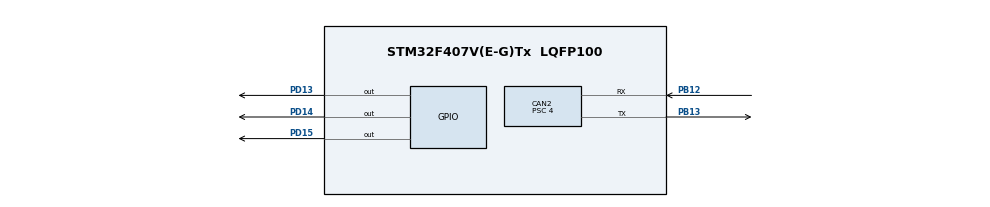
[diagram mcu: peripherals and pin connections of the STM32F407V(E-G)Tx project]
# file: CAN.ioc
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CAN2.BS1=CAN_BS1_8TQ
CAN2.BS2=CAN_BS2_7TQ
CAN2.CalculateBaudRate=250000
CAN2.CalculateTimeBit=4000
CAN2.CalculateTimeQuantum=250.0
CAN2.Prescaler=4
Mcu.Family=STM32F4
Mcu.Name=STM32F407V(E-G)Tx
Mcu.Package=LQFP100
NVIC.CAN2_RX0_IRQn=true\:0\:0\:false\:false\:true\:true\:true\:true
NVIC.PriorityGroup=NVIC_PRIORITYGROUP_4
PB12.Mode=CAN_Activate
PB12.Signal=CAN2_RX
PB13.Mode=CAN_Activate
PB13.Signal=CAN2_TX
PD13.Signal=GPIO_Output
PD14.Signal=GPIO_Output
PD15.Signal=GPIO_Output
ProjectManager.HeapSize=0x200
ProjectManager.StackSize=0x400
ProjectManager.TargetToolchain=STM32CubeIDE
RCC.AHBFreq_Value=16000000
RCC.APB1Freq_Value=16000000
RCC.APB2Freq_Value=16000000
RCC.CortexFreq_Value=16000000
RCC.HSE_VALUE=25000000
RCC.HSI_VALUE=16000000
RCC.LSE_VALUE=32768
RCC.SYSCLKFreq_VALUE=16000000
RCC.VCOOutputFreq_Value=192000000
board=custom

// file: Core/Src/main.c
/* USER CODE BEGIN Header */
/**
  ******************************************************************************
  * @file           : main.c
  * @brief          : Main program body
  ******************************************************************************
  * @attention
  *
  * Copyright (c) 2023 STMicroelectronics.
  * All rights reserved.
  *
  * This software is licensed under terms that can be found in the LICENSE file
  * in the root directory of this software component.
  * If no LICENSE file comes with this software, it is provided AS-IS.
  *
  ******************************************************************************
  */
/* USER CODE END Header */
#include "main.h"

CAN_HandleTypeDef hcan2;

/* USER CODE BEGIN PV */

// We need to define the CAN transmit header
// & the array that will contain the data to transmit
// & the mailbox where the data is added to before being sent
CAN_TxHeaderTypeDef   TxHeader;
CAN_RxHeaderTypeDef   RxHeader;

uint8_t               TxData[8];
uint32_t              TxMailbox;
uint8_t               RxData[8];
/* USER CODE END PV */

void SystemClock_Config(void);
static void MX_GPIO_Init(void);
static void MX_CAN2_Init(void);

/* USER CODE BEGIN 0 */

void HAL_CAN_RxFifo0MsgPendingCallback(CAN_HandleTypeDef *hcan2)
{
  if (HAL_CAN_GetRxMessage(hcan2, CAN_RX_FIFO0, &RxHeader, RxData) != HAL_OK)
  {
    Error_Handler();
  }

  HAL_GPIO_TogglePin(GPIOD,GPIO_PIN_13);
  TxData[0] = RxData[0];

  if (HAL_CAN_AddTxMessage(hcan2, &TxHeader, TxData, &TxMailbox) != HAL_OK)
  	  {
  		/* Transmission request Error */
  		Error_Handler();
  	  }

}

/* USER CODE END 0 */

int main(void)
{
  /* USER CODE BEGIN 1 */

	// The CAN clock must be enabled
  __HAL_RCC_CAN2_CLK_ENABLE();

  /* USER CODE END 1 */

  /* MCU Configuration--------------------------------------------------------*/

  /* Reset of all peripherals, Initializes the Flash interface and the Systick. */
  HAL_Init();

  /* Configure the system clock */
  SystemClock_Config();

  /* Initialize all configured peripherals */
  MX_GPIO_Init();
  MX_CAN2_Init();

  /* Infinite loop */
  /* USER CODE BEGIN WHILE */
  while (1)
  {

//	  // Enable channel
//	  TxData[0] = 0x1C;
//
//	  /* Start the Transmission process */
//	  // By using the HAL_CAN_ADD_TxMessage(args), a CAN message will try to be sent
//	  if (HAL_CAN_AddTxMessage(&hcan2, &TxHeader, TxData, &TxMailbox) != HAL_OK)
//	  {
//		/* Transmission request Error */
//		Error_Handler();
//	  }
	  HAL_GPIO_TogglePin(GPIOD, GPIO_PIN_13);
	  HAL_Delay(1);

    /* USER CODE END WHILE */

  }
}

void SystemClock_Config(void)
{
  RCC_OscInitTypeDef RCC_OscInitStruct = {0};
  RCC_ClkInitTypeDef RCC_ClkInitStruct = {0};

  /** Configure the main internal regulator output voltage
  */
  __HAL_RCC_PWR_CLK_ENABLE();
  __HAL_PWR_VOLTAGESCALING_CONFIG(PWR_REGULATOR_VOLTAGE_SCALE1);

  /** Initializes the RCC Oscillators according to the specified parameters
  * in the RCC_OscInitTypeDef structure.
  */
  RCC_OscInitStruct.OscillatorType = RCC_OSCILLATORTYPE_HSI|RCC_OSCILLATORTYPE_HSE;
  RCC_OscInitStruct.HSEState = RCC_HSE_ON;
  RCC_OscInitStruct.HSIState = RCC_HSI_ON;
  RCC_OscInitStruct.HSICalibrationValue = RCC_HSICALIBRATION_DEFAULT;
  RCC_OscInitStruct.PLL.PLLState = RCC_PLL_ON;
  RCC_OscInitStruct.PLL.PLLSource = RCC_PLLSOURCE_HSE;
  RCC_OscInitStruct.PLL.PLLM = 4;
  RCC_OscInitStruct.PLL.PLLN = 168;
  RCC_OscInitStruct.PLL.PLLP = RCC_PLLP_DIV2;
  RCC_OscInitStruct.PLL.PLLQ = 4;
  if (HAL_RCC_OscConfig(&RCC_OscInitStruct) != HAL_OK)
  {
    Error_Handler();
  }

  /** Initializes the CPU, AHB and APB buses clocks
  */
  RCC_ClkInitStruct.ClockType = RCC_CLOCKTYPE_HCLK|RCC_CLOCKTYPE_SYSCLK
                              |RCC_CLOCKTYPE_PCLK1|RCC_CLOCKTYPE_PCLK2;
  RCC_ClkInitStruct.SYSCLKSource = RCC_SYSCLKSOURCE_PLLCLK;
  RCC_ClkInitStruct.AHBCLKDivider = RCC_SYSCLK_DIV1;
  RCC_ClkInitStruct.APB1CLKDivider = RCC_HCLK_DIV4;
  RCC_ClkInitStruct.APB2CLKDivider = RCC_HCLK_DIV2;

  if (HAL_RCC_ClockConfig(&RCC_ClkInitStruct, FLASH_LATENCY_5) != HAL_OK)
  {
    Error_Handler();
  }
  HAL_RCC_MCOConfig(RCC_MCO1, RCC_MCO1SOURCE_HSI, RCC_MCODIV_1);

  /** Enables the Clock Security System
  */
  HAL_RCC_EnableCSS();
}

static void MX_CAN2_Init(void)
{

  /* USER CODE BEGIN CAN2_Init 0 */
	// Configure the GPIO pins for CAN2
	GPIO_InitTypeDef GPIO_InitStruct = {0};
	GPIO_InitStruct.Pin = GPIO_PIN_13 | GPIO_PIN_12;
	GPIO_InitStruct.Mode = GPIO_MODE_AF_PP;
	GPIO_InitStruct.Pull = GPIO_NOPULL;
	GPIO_InitStruct.Speed = GPIO_SPEED_FREQ_VERY_HIGH;
	GPIO_InitStruct.Alternate = GPIO_AF9_CAN2;
  /* USER CODE END CAN2_Init 0 */

  /* USER CODE BEGIN CAN2_Init 1 */

	// We need to initialize the pins
	HAL_GPIO_Init(GPIOB, &GPIO_InitStruct);
  /* USER CODE END CAN2_Init 1 */
  hcan2.Instance = CAN2;
  hcan2.Init.Prescaler = 12;
  hcan2.Init.Mode = CAN_MODE_NORMAL;
  hcan2.Init.SyncJumpWidth = CAN_SJW_1TQ;
  hcan2.Init.TimeSeg1 = CAN_BS1_7TQ;
  hcan2.Init.TimeSeg2 = CAN_BS2_6TQ;
  hcan2.Init.TimeTriggeredMode = DISABLE;
  hcan2.Init.AutoBusOff = DISABLE;
  hcan2.Init.AutoWakeUp = DISABLE;
  hcan2.Init.AutoRetransmission = DISABLE;
  hcan2.Init.ReceiveFifoLocked = DISABLE;
  hcan2.Init.TransmitFifoPriority = DISABLE;
  if (HAL_CAN_Init(&hcan2) != HAL_OK)
  {
    Error_Handler();
  }
  /* USER CODE BEGIN CAN2_Init 2 */

  // CAN Filter
  CAN_FilterTypeDef FilterConfig;

   TxHeader.DLC=1; //give message size of 1 byte
   TxHeader.IDE=CAN_ID_STD; //set identifier to standard
   TxHeader.RTR=CAN_RTR_DATA; //set data type to remote transmission request?
   TxHeader.StdId=0x244; //define a standard identifier, used for message identification by filters (switch this for the other microcontroller)
   TxHeader.ExtId = 0x01;
   TxHeader.TransmitGlobalTime = DISABLE;

  //filter one (stack light blink)
   FilterConfig.FilterFIFOAssignment=CAN_RX_FIFO0; //set fifo assignment
   FilterConfig.FilterIdHigh = 0x0000;
   FilterConfig.FilterIdLow = 0x0000;
   FilterConfig.FilterMaskIdHigh = 0x0000;
   FilterConfig.FilterMaskIdLow = 0x0000;
   FilterConfig.FilterScale=CAN_FILTERSCALE_32BIT; //set filter scale
   FilterConfig.FilterActivation=ENABLE;
   FilterConfig.FilterBank = 0;
   FilterConfig.FilterMode = CAN_FILTERMODE_IDMASK;
   FilterConfig.SlaveStartFilterBank = 14;
   FilterConfig.FilterBank = 14;
   if (HAL_CAN_ConfigFilter(&hcan2, &FilterConfig) != HAL_OK)

    {

     /* Filter configuration Error */

     Error_Handler();

    }
  	/*##-3- Start the CAN peripheral ###########################################*/
	  if (HAL_CAN_ActivateNotification(&hcan2, CAN_IT_RX_FIFO0_MSG_PENDING) != HAL_OK)
		 {
		  Error_Handler();
		 }
  	  // If HAL_CAN_Start returns an error, then we want to go into the error handler
    if (HAL_CAN_Start(&hcan2) != HAL_OK)
  	{
       /* Start Error */
       Error_Handler();
  	}
  	//Configure transmission process
    // This is where we set the ID and data length and other misc. CAN bits
  	TxHeader.StdId = 0x710;
  	TxHeader.ExtId = 0x01;
  	TxHeader.RTR = CAN_RTR_DATA;
  	TxHeader.IDE = CAN_ID_STD;
  	TxHeader.DLC = 1;
  	TxHeader.TransmitGlobalTime = DISABLE;

  /* USER CODE END CAN2_Init 2 */

}

static void MX_GPIO_Init(void)
{
  GPIO_InitTypeDef GPIO_InitStruct = {0};

  /* GPIO Ports Clock Enable */
  __HAL_RCC_GPIOH_CLK_ENABLE();
  __HAL_RCC_GPIOB_CLK_ENABLE();
  __HAL_RCC_GPIOD_CLK_ENABLE();
  __HAL_RCC_GPIOA_CLK_ENABLE();

  /*Configure GPIO pin Output Level */
  HAL_GPIO_WritePin(GPIOD, GPIO_PIN_13|GPIO_PIN_14|GPIO_PIN_15, GPIO_PIN_RESET);

  /*Configure GPIO pins : PD13 PD14 PD15 */
  GPIO_InitStruct.Pin = GPIO_PIN_13|GPIO_PIN_14|GPIO_PIN_15;
  GPIO_InitStruct.Mode = GPIO_MODE_OUTPUT_PP;
  GPIO_InitStruct.Pull = GPIO_NOPULL;
  GPIO_InitStruct.Speed = GPIO_SPEED_FREQ_LOW;
  HAL_GPIO_Init(GPIOD, &GPIO_InitStruct);

  /*Configure GPIO pin : PA8 */
  GPIO_InitStruct.Pin = GPIO_PIN_8;
  GPIO_InitStruct.Mode = GPIO_MODE_AF_PP;
  GPIO_InitStruct.Pull = GPIO_NOPULL;
  GPIO_InitStruct.Speed = GPIO_SPEED_FREQ_LOW;
  GPIO_InitStruct.Alternate = GPIO_AF0_MCO;
  HAL_GPIO_Init(GPIOA, &GPIO_InitStruct);

}

void Error_Handler(void)
{
  /* USER CODE BEGIN Error_Handler_Debug */
  /* User can add his own implementation to report the HAL error return state */
  __disable_irq();
  HAL_GPIO_WritePin(GPIOD, GPIO_PIN_15, GPIO_PIN_SET);
  while (1)
  {
  }
  /* USER CODE END Error_Handler_Debug */
}
